VERSION 5.7 ;
  NOWIREEXTENSIONATPIN ON ;
  DIVIDERCHAR "/" ;
  BUSBITCHARS "[]" ;
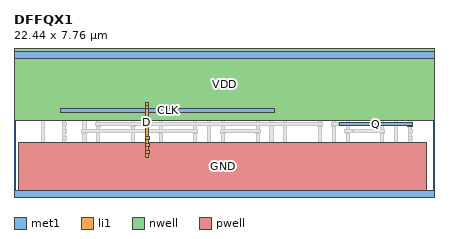
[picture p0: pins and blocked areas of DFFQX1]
MACRO DFFQX1
  CLASS CORE ;
  FOREIGN DFFQX1 ;
  ORIGIN 0.000 0.000 ;
  SIZE 22.440 BY 7.760 ;
  SYMMETRY X Y ;
  SITE unitrh ;
  PIN Q
    DIRECTION OUTPUT ;
    USE SIGNAL ;
    ANTENNADIFFAREA 1.351900 ;
    PORT
      LAYER met1 ;
        RECT 21.040 3.965 21.270 3.995 ;
        RECT 17.405 3.795 21.300 3.965 ;
        RECT 21.040 3.765 21.270 3.795 ;
    END
  END Q
  PIN D
    DIRECTION INPUT ;
    USE SIGNAL ;
    ANTENNAGATEAREA 1.027250 ;
    PORT
      LAYER li1 ;
        RECT 7.040 4.890 7.210 5.045 ;
        RECT 7.010 4.715 7.210 4.890 ;
        RECT 7.010 3.225 7.180 4.715 ;
        RECT 7.010 3.055 7.235 3.225 ;
        RECT 7.010 2.855 7.180 3.055 ;
        RECT 7.010 2.685 7.235 2.855 ;
        RECT 7.010 2.485 7.180 2.685 ;
        RECT 7.010 2.315 7.235 2.485 ;
        RECT 7.010 2.095 7.180 2.315 ;
    END
  END D
  PIN CLK
    DIRECTION INPUT ;
    USE SIGNAL ;
    ANTENNAGATEAREA 2.042100 ;
    PORT
      LAYER met1 ;
        RECT 2.540 4.705 2.770 4.735 ;
        RECT 13.640 4.705 13.870 4.735 ;
        RECT 2.510 4.535 13.900 4.705 ;
        RECT 2.540 4.505 2.770 4.535 ;
        RECT 13.640 4.505 13.870 4.535 ;
    END
  END CLK
  PIN VDD
    DIRECTION INOUT ;
    USE POWER ;
    SHAPE ABUTMENT ;
    PORT
      LAYER nwell ;
        RECT 0.000 4.110 22.440 7.940 ;
      LAYER met1 ;
        RECT 0.000 7.410 22.440 7.760 ;
    END
  END VDD
  PIN GND
    DIRECTION INOUT ;
    USE GROUND ;
    SHAPE ABUTMENT ;
    PORT
      LAYER pwell ;
        RECT 0.265 0.350 22.065 2.900 ;
        RECT 0.000 0.000 22.440 0.350 ;
      LAYER met1 ;
        RECT 0.000 0.000 22.440 0.350 ;
    END
  END GND
  OBS
      LAYER li1 ;
        RECT 0.000 7.410 22.440 7.760 ;
        RECT 0.265 4.290 0.605 7.410 ;
        RECT 1.440 5.395 1.610 7.410 ;
        RECT 1.880 5.420 2.050 7.200 ;
        RECT 2.320 5.735 2.490 7.410 ;
        RECT 2.760 5.420 2.930 7.200 ;
        RECT 3.200 5.735 3.370 7.410 ;
        RECT 3.640 5.420 3.810 7.200 ;
        RECT 4.080 5.735 4.250 7.410 ;
        RECT 1.880 5.250 4.590 5.420 ;
        RECT 0.265 0.350 0.605 2.900 ;
        RECT 1.460 2.095 1.630 5.045 ;
        RECT 2.570 4.705 2.740 5.045 ;
        RECT 2.570 4.535 2.795 4.705 ;
        RECT 2.570 3.965 2.740 4.535 ;
        RECT 2.570 3.795 2.795 3.965 ;
        RECT 2.570 3.595 2.740 3.795 ;
        RECT 2.570 3.425 2.795 3.595 ;
        RECT 2.570 3.225 2.740 3.425 ;
        RECT 2.570 3.055 2.795 3.225 ;
        RECT 2.570 2.855 2.740 3.055 ;
        RECT 2.570 2.685 2.795 2.855 ;
        RECT 2.570 2.095 2.740 2.685 ;
        RECT 3.680 2.095 3.850 5.045 ;
        RECT 0.940 1.855 1.110 1.935 ;
        RECT 1.910 1.855 2.080 1.935 ;
        RECT 2.880 1.855 3.050 1.935 ;
        RECT 0.940 1.685 3.050 1.855 ;
        RECT 0.940 0.555 1.110 1.685 ;
        RECT 1.425 0.350 1.595 1.310 ;
        RECT 1.910 0.805 2.080 1.685 ;
        RECT 2.880 1.605 3.050 1.685 ;
        RECT 2.400 1.260 2.570 1.340 ;
        RECT 3.450 1.260 3.620 1.935 ;
        RECT 4.420 1.930 4.590 5.250 ;
        RECT 5.075 4.290 5.415 7.410 ;
        RECT 5.950 5.315 6.120 7.410 ;
        RECT 6.390 5.465 6.560 7.200 ;
        RECT 6.830 5.735 7.000 7.410 ;
        RECT 7.270 5.465 7.440 7.200 ;
        RECT 7.710 5.735 7.880 7.410 ;
        RECT 6.390 5.295 7.920 5.465 ;
        RECT 2.400 1.090 3.620 1.260 ;
        RECT 2.400 1.010 2.570 1.090 ;
        RECT 2.880 0.805 3.050 0.885 ;
        RECT 1.910 0.635 3.050 0.805 ;
        RECT 1.910 0.555 2.080 0.635 ;
        RECT 2.880 0.555 3.050 0.635 ;
        RECT 3.450 0.805 3.620 1.090 ;
        RECT 3.935 1.760 4.590 1.930 ;
        RECT 3.935 1.025 4.105 1.760 ;
        RECT 4.420 0.805 4.590 1.575 ;
        RECT 3.450 0.635 4.590 0.805 ;
        RECT 3.450 0.555 3.620 0.635 ;
        RECT 4.420 0.555 4.590 0.635 ;
        RECT 5.075 0.350 5.415 2.900 ;
        RECT 6.270 2.095 6.440 5.045 ;
        RECT 5.855 1.845 6.025 1.925 ;
        RECT 6.825 1.845 6.995 1.925 ;
        RECT 7.750 1.920 7.920 5.295 ;
        RECT 8.405 4.290 8.745 7.410 ;
        RECT 9.280 5.315 9.450 7.410 ;
        RECT 9.720 5.465 9.890 7.200 ;
        RECT 10.160 5.735 10.330 7.410 ;
        RECT 10.600 5.465 10.770 7.200 ;
        RECT 11.040 5.735 11.210 7.410 ;
        RECT 9.720 5.295 11.250 5.465 ;
        RECT 5.855 1.675 6.995 1.845 ;
        RECT 5.855 0.545 6.025 1.675 ;
        RECT 6.340 0.350 6.510 1.300 ;
        RECT 6.825 0.795 6.995 1.675 ;
        RECT 7.310 1.750 7.920 1.920 ;
        RECT 7.310 1.015 7.480 1.750 ;
        RECT 7.795 0.795 7.965 1.565 ;
        RECT 6.825 0.625 7.965 0.795 ;
        RECT 6.825 0.545 6.995 0.625 ;
        RECT 7.795 0.545 7.965 0.625 ;
        RECT 8.405 0.350 8.745 2.900 ;
        RECT 9.600 2.095 9.770 5.045 ;
        RECT 10.370 4.890 10.540 5.045 ;
        RECT 10.340 4.715 10.540 4.890 ;
        RECT 10.340 2.095 10.510 4.715 ;
        RECT 9.185 1.845 9.355 1.925 ;
        RECT 10.155 1.845 10.325 1.925 ;
        RECT 11.080 1.920 11.250 5.295 ;
        RECT 11.735 4.290 12.075 7.410 ;
        RECT 12.610 5.315 12.780 7.410 ;
        RECT 13.050 5.465 13.220 7.200 ;
        RECT 13.490 5.735 13.660 7.410 ;
        RECT 13.930 5.465 14.100 7.200 ;
        RECT 14.370 5.735 14.540 7.410 ;
        RECT 13.050 5.295 14.580 5.465 ;
        RECT 9.185 1.675 10.325 1.845 ;
        RECT 9.185 0.545 9.355 1.675 ;
        RECT 9.670 0.350 9.840 1.300 ;
        RECT 10.155 0.795 10.325 1.675 ;
        RECT 10.640 1.750 11.250 1.920 ;
        RECT 10.640 1.015 10.810 1.750 ;
        RECT 11.125 0.795 11.295 1.565 ;
        RECT 10.155 0.625 11.295 0.795 ;
        RECT 10.155 0.545 10.325 0.625 ;
        RECT 11.125 0.545 11.295 0.625 ;
        RECT 11.735 0.350 12.075 2.900 ;
        RECT 12.930 2.095 13.100 5.045 ;
        RECT 13.700 4.890 13.870 5.045 ;
        RECT 13.670 4.715 13.870 4.890 ;
        RECT 13.670 2.095 13.840 4.715 ;
        RECT 12.515 1.845 12.685 1.925 ;
        RECT 13.485 1.845 13.655 1.925 ;
        RECT 14.410 1.920 14.580 5.295 ;
        RECT 15.065 4.290 15.405 7.410 ;
        RECT 15.940 5.315 16.110 7.410 ;
        RECT 16.380 5.465 16.550 7.200 ;
        RECT 16.820 5.735 16.990 7.410 ;
        RECT 17.260 5.465 17.430 7.200 ;
        RECT 17.700 5.735 17.870 7.410 ;
        RECT 16.380 5.295 17.910 5.465 ;
        RECT 12.515 1.675 13.655 1.845 ;
        RECT 12.515 0.545 12.685 1.675 ;
        RECT 13.000 0.350 13.170 1.300 ;
        RECT 13.485 0.795 13.655 1.675 ;
        RECT 13.970 1.750 14.580 1.920 ;
        RECT 13.970 1.015 14.140 1.750 ;
        RECT 14.455 0.795 14.625 1.565 ;
        RECT 13.485 0.625 14.625 0.795 ;
        RECT 13.485 0.545 13.655 0.625 ;
        RECT 14.455 0.545 14.625 0.625 ;
        RECT 15.065 0.350 15.405 2.900 ;
        RECT 16.260 2.095 16.430 5.045 ;
        RECT 17.030 4.890 17.200 5.045 ;
        RECT 17.000 4.715 17.200 4.890 ;
        RECT 17.000 2.095 17.170 4.715 ;
        RECT 15.845 1.845 16.015 1.925 ;
        RECT 16.815 1.845 16.985 1.925 ;
        RECT 17.740 1.920 17.910 5.295 ;
        RECT 18.395 4.290 18.735 7.410 ;
        RECT 19.270 5.315 19.440 7.410 ;
        RECT 19.710 5.465 19.880 7.200 ;
        RECT 20.150 5.735 20.320 7.410 ;
        RECT 20.590 5.465 20.760 7.200 ;
        RECT 21.030 5.735 21.200 7.410 ;
        RECT 19.710 5.295 21.240 5.465 ;
        RECT 21.070 5.075 21.240 5.295 ;
        RECT 15.845 1.675 16.985 1.845 ;
        RECT 15.845 0.545 16.015 1.675 ;
        RECT 16.330 0.350 16.500 1.300 ;
        RECT 16.815 0.795 16.985 1.675 ;
        RECT 17.300 1.750 17.910 1.920 ;
        RECT 17.300 1.015 17.470 1.750 ;
        RECT 17.785 0.795 17.955 1.565 ;
        RECT 16.815 0.625 17.955 0.795 ;
        RECT 16.815 0.545 16.985 0.625 ;
        RECT 17.785 0.545 17.955 0.625 ;
        RECT 18.395 0.350 18.735 2.900 ;
        RECT 19.590 2.095 19.760 5.045 ;
        RECT 20.360 4.890 20.530 5.045 ;
        RECT 20.330 4.715 20.530 4.890 ;
        RECT 21.070 4.905 21.295 5.075 ;
        RECT 20.330 2.095 20.500 4.715 ;
        RECT 21.070 4.705 21.240 4.905 ;
        RECT 21.070 4.535 21.295 4.705 ;
        RECT 21.070 4.335 21.240 4.535 ;
        RECT 21.070 4.165 21.295 4.335 ;
        RECT 21.725 4.290 22.065 7.410 ;
        RECT 21.070 3.965 21.240 4.165 ;
        RECT 21.070 3.795 21.295 3.965 ;
        RECT 21.070 3.595 21.240 3.795 ;
        RECT 21.070 3.425 21.295 3.595 ;
        RECT 21.070 3.225 21.240 3.425 ;
        RECT 21.070 3.055 21.295 3.225 ;
        RECT 21.070 2.855 21.240 3.055 ;
        RECT 21.070 2.685 21.295 2.855 ;
        RECT 21.070 2.485 21.240 2.685 ;
        RECT 21.070 2.315 21.295 2.485 ;
        RECT 19.175 1.845 19.345 1.925 ;
        RECT 20.145 1.845 20.315 1.925 ;
        RECT 21.070 1.920 21.240 2.315 ;
        RECT 19.175 1.675 20.315 1.845 ;
        RECT 19.175 0.545 19.345 1.675 ;
        RECT 19.660 0.350 19.830 1.300 ;
        RECT 20.145 0.795 20.315 1.675 ;
        RECT 20.630 1.750 21.240 1.920 ;
        RECT 20.630 1.015 20.800 1.750 ;
        RECT 21.115 0.795 21.285 1.565 ;
        RECT 20.145 0.625 21.285 0.795 ;
        RECT 20.145 0.545 20.315 0.625 ;
        RECT 21.115 0.545 21.285 0.625 ;
        RECT 21.725 0.350 22.065 2.900 ;
        RECT 0.000 0.000 22.440 0.350 ;
      LAYER mcon ;
        RECT 0.720 7.495 0.890 7.665 ;
        RECT 1.090 7.495 1.260 7.665 ;
        RECT 1.460 7.495 1.630 7.665 ;
        RECT 1.830 7.495 2.000 7.665 ;
        RECT 2.200 7.495 2.370 7.665 ;
        RECT 2.570 7.495 2.740 7.665 ;
        RECT 2.940 7.495 3.110 7.665 ;
        RECT 3.310 7.495 3.480 7.665 ;
        RECT 3.680 7.495 3.850 7.665 ;
        RECT 4.050 7.495 4.220 7.665 ;
        RECT 4.420 7.495 4.590 7.665 ;
        RECT 4.790 7.495 4.960 7.665 ;
        RECT 5.530 7.495 5.700 7.665 ;
        RECT 5.900 7.495 6.070 7.665 ;
        RECT 6.270 7.495 6.440 7.665 ;
        RECT 6.640 7.495 6.810 7.665 ;
        RECT 7.010 7.495 7.180 7.665 ;
        RECT 7.380 7.495 7.550 7.665 ;
        RECT 7.750 7.495 7.920 7.665 ;
        RECT 8.120 7.495 8.290 7.665 ;
        RECT 8.860 7.495 9.030 7.665 ;
        RECT 9.230 7.495 9.400 7.665 ;
        RECT 9.600 7.495 9.770 7.665 ;
        RECT 9.970 7.495 10.140 7.665 ;
        RECT 10.340 7.495 10.510 7.665 ;
        RECT 10.710 7.495 10.880 7.665 ;
        RECT 11.080 7.495 11.250 7.665 ;
        RECT 11.450 7.495 11.620 7.665 ;
        RECT 12.190 7.495 12.360 7.665 ;
        RECT 12.560 7.495 12.730 7.665 ;
        RECT 12.930 7.495 13.100 7.665 ;
        RECT 13.300 7.495 13.470 7.665 ;
        RECT 13.670 7.495 13.840 7.665 ;
        RECT 14.040 7.495 14.210 7.665 ;
        RECT 14.410 7.495 14.580 7.665 ;
        RECT 14.780 7.495 14.950 7.665 ;
        RECT 15.520 7.495 15.690 7.665 ;
        RECT 15.890 7.495 16.060 7.665 ;
        RECT 16.260 7.495 16.430 7.665 ;
        RECT 16.630 7.495 16.800 7.665 ;
        RECT 17.000 7.495 17.170 7.665 ;
        RECT 17.370 7.495 17.540 7.665 ;
        RECT 17.740 7.495 17.910 7.665 ;
        RECT 18.110 7.495 18.280 7.665 ;
        RECT 18.850 7.495 19.020 7.665 ;
        RECT 19.220 7.495 19.390 7.665 ;
        RECT 19.590 7.495 19.760 7.665 ;
        RECT 19.960 7.495 20.130 7.665 ;
        RECT 20.330 7.495 20.500 7.665 ;
        RECT 20.700 7.495 20.870 7.665 ;
        RECT 21.070 7.495 21.240 7.665 ;
        RECT 21.440 7.495 21.610 7.665 ;
        RECT 1.460 4.165 1.630 4.335 ;
        RECT 3.680 3.425 3.850 3.595 ;
        RECT 4.420 3.795 4.590 3.965 ;
        RECT 6.270 3.795 6.440 3.965 ;
        RECT 7.750 3.425 7.920 3.595 ;
        RECT 9.600 3.425 9.770 3.595 ;
        RECT 10.340 4.165 10.510 4.335 ;
        RECT 11.080 3.425 11.250 3.595 ;
        RECT 12.930 3.425 13.100 3.595 ;
        RECT 13.670 4.535 13.840 4.705 ;
        RECT 14.410 4.165 14.580 4.335 ;
        RECT 16.260 3.795 16.430 3.965 ;
        RECT 17.000 3.795 17.170 3.965 ;
        RECT 17.740 3.425 17.910 3.595 ;
        RECT 19.590 3.425 19.760 3.595 ;
        RECT 20.330 4.165 20.500 4.335 ;
        RECT 0.720 0.095 0.890 0.265 ;
        RECT 1.090 0.095 1.260 0.265 ;
        RECT 1.460 0.095 1.630 0.265 ;
        RECT 1.830 0.095 2.000 0.265 ;
        RECT 2.200 0.095 2.370 0.265 ;
        RECT 2.570 0.095 2.740 0.265 ;
        RECT 2.940 0.095 3.110 0.265 ;
        RECT 3.310 0.095 3.480 0.265 ;
        RECT 3.680 0.095 3.850 0.265 ;
        RECT 4.050 0.095 4.220 0.265 ;
        RECT 4.420 0.095 4.590 0.265 ;
        RECT 4.790 0.095 4.960 0.265 ;
        RECT 5.530 0.095 5.700 0.265 ;
        RECT 5.900 0.095 6.070 0.265 ;
        RECT 6.270 0.095 6.440 0.265 ;
        RECT 6.640 0.095 6.810 0.265 ;
        RECT 7.010 0.095 7.180 0.265 ;
        RECT 7.380 0.095 7.550 0.265 ;
        RECT 7.750 0.095 7.920 0.265 ;
        RECT 8.120 0.095 8.290 0.265 ;
        RECT 8.860 0.095 9.030 0.265 ;
        RECT 9.230 0.095 9.400 0.265 ;
        RECT 9.600 0.095 9.770 0.265 ;
        RECT 9.970 0.095 10.140 0.265 ;
        RECT 10.340 0.095 10.510 0.265 ;
        RECT 10.710 0.095 10.880 0.265 ;
        RECT 11.080 0.095 11.250 0.265 ;
        RECT 11.450 0.095 11.620 0.265 ;
        RECT 12.190 0.095 12.360 0.265 ;
        RECT 12.560 0.095 12.730 0.265 ;
        RECT 12.930 0.095 13.100 0.265 ;
        RECT 13.300 0.095 13.470 0.265 ;
        RECT 13.670 0.095 13.840 0.265 ;
        RECT 14.040 0.095 14.210 0.265 ;
        RECT 14.410 0.095 14.580 0.265 ;
        RECT 14.780 0.095 14.950 0.265 ;
        RECT 15.520 0.095 15.690 0.265 ;
        RECT 15.890 0.095 16.060 0.265 ;
        RECT 16.260 0.095 16.430 0.265 ;
        RECT 16.630 0.095 16.800 0.265 ;
        RECT 17.000 0.095 17.170 0.265 ;
        RECT 17.370 0.095 17.540 0.265 ;
        RECT 17.740 0.095 17.910 0.265 ;
        RECT 18.110 0.095 18.280 0.265 ;
        RECT 18.850 0.095 19.020 0.265 ;
        RECT 19.220 0.095 19.390 0.265 ;
        RECT 19.590 0.095 19.760 0.265 ;
        RECT 19.960 0.095 20.130 0.265 ;
        RECT 20.330 0.095 20.500 0.265 ;
        RECT 20.700 0.095 20.870 0.265 ;
        RECT 21.070 0.095 21.240 0.265 ;
        RECT 21.440 0.095 21.610 0.265 ;
      LAYER met1 ;
        RECT 1.430 4.335 1.660 4.365 ;
        RECT 10.310 4.335 10.540 4.365 ;
        RECT 14.380 4.335 14.610 4.365 ;
        RECT 20.300 4.335 20.530 4.365 ;
        RECT 1.400 4.165 20.560 4.335 ;
        RECT 1.430 4.135 1.660 4.165 ;
        RECT 10.310 4.135 10.540 4.165 ;
        RECT 14.380 4.135 14.610 4.165 ;
        RECT 20.300 4.135 20.530 4.165 ;
        RECT 4.390 3.965 4.620 3.995 ;
        RECT 6.240 3.965 6.470 3.995 ;
        RECT 16.230 3.965 16.460 3.995 ;
        RECT 16.970 3.965 17.200 3.995 ;
        RECT 4.360 3.795 16.490 3.965 ;
        RECT 16.940 3.795 17.350 3.965 ;
        RECT 4.390 3.765 4.620 3.795 ;
        RECT 6.240 3.765 6.470 3.795 ;
        RECT 16.230 3.765 16.460 3.795 ;
        RECT 16.970 3.765 17.200 3.795 ;
        RECT 3.650 3.595 3.880 3.625 ;
        RECT 7.720 3.595 7.950 3.625 ;
        RECT 9.570 3.595 9.800 3.625 ;
        RECT 11.050 3.595 11.280 3.625 ;
        RECT 12.900 3.595 13.130 3.625 ;
        RECT 17.710 3.595 17.940 3.625 ;
        RECT 19.560 3.595 19.790 3.625 ;
        RECT 3.620 3.425 9.830 3.595 ;
        RECT 11.020 3.425 13.160 3.595 ;
        RECT 17.680 3.425 18.090 3.595 ;
        RECT 18.145 3.425 19.820 3.595 ;
        RECT 3.650 3.395 3.880 3.425 ;
        RECT 7.720 3.395 7.950 3.425 ;
        RECT 9.570 3.395 9.800 3.425 ;
        RECT 11.050 3.395 11.280 3.425 ;
        RECT 12.900 3.395 13.130 3.425 ;
        RECT 17.710 3.395 17.940 3.425 ;
        RECT 19.560 3.395 19.790 3.425 ;
  END
END DFFQX1
END LIBRARY

